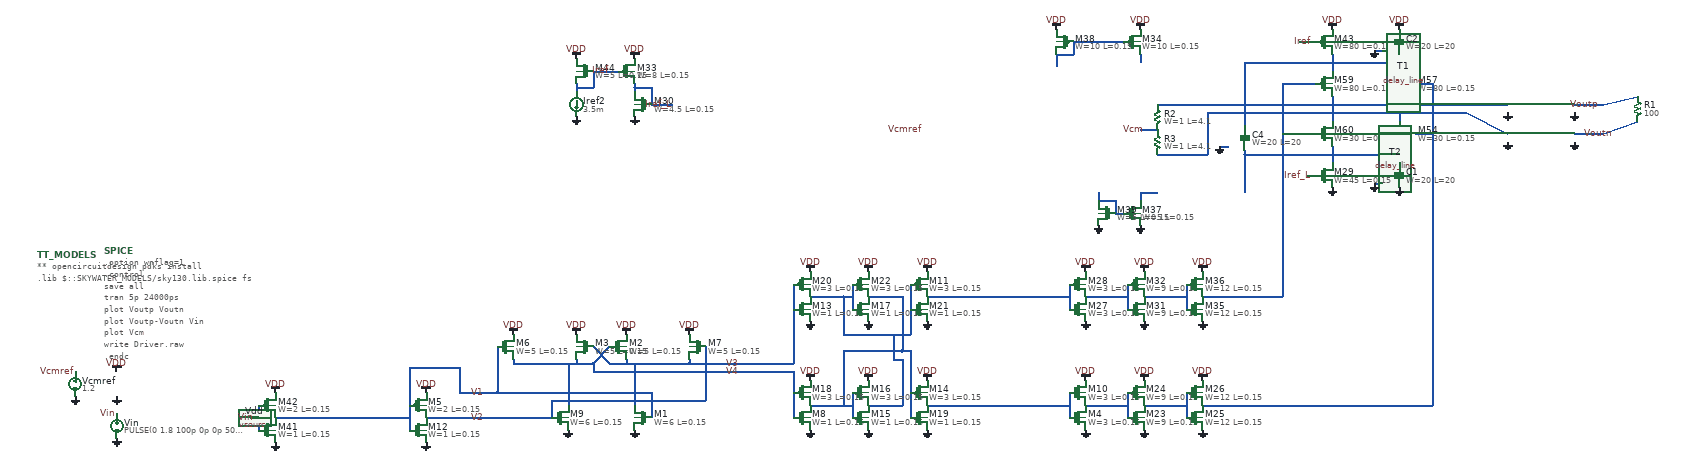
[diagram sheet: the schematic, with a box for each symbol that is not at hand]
v {xschem version=3.4.2 file_version=1.2
}
G {}
K {}
V {}
S {}
E {}
N 810 -140 1180 -140 {
lab=V2}
N 810 -140 810 -100 {
lab=V2}
N 680 -160 1050 -160 {
lab=V1}
N 1050 -160 1050 -100 {
lab=V1}
N 590 -100 810 -100 {
lab=V2}
N 590 -160 680 -160 {
lab=V1}
N 470 -130 470 -70 {
lab=V1}
N 390 -100 470 -100 {
lab=V1}
N 510 -100 590 -100 {
lab=V2}
N 470 -220 470 -130 {
lab=V1}
N 470 -220 590 -220 {
lab=V1}
N 590 -220 590 -160 {
lab=V1}
N 850 -190 850 -130 {
lab=V4}
N 1010 -190 1010 -130 {
lab=V3}
N 1390 -160 1390 -100 {
lab=V4}
N 1530 -160 1530 -100 {
lab=#net1}
N 1670 -160 1670 -100 {
lab=#net1}
N 1430 -130 1530 -130 {
lab=#net1}
N 1570 -130 1650 -130 {
lab=#net2}
N 1710 -130 1910 -130 {
lab=#net3}
N 720 -230 870 -230 {
lab=V4}
N 910 -270 950 -230 {
lab=V3}
N 910 -230 950 -270 {
lab=V4}
N 870 -230 910 -230 {
lab=V4}
N 990 -230 1140 -230 {
lab=V3}
N 950 -230 990 -230 {
lab=V3}
N 1010 -230 1010 -190 {
lab=V3}
N 850 -230 850 -190 {
lab=V4}
N 990 -240 990 -230 {
lab=V3}
N 870 -240 870 -230 {
lab=V4}
N 720 -240 720 -230 {
lab=V4}
N 1140 -240 1140 -230 {
lab=V3}
N 910 -230 910 -210 {
lab=V4}
N 1140 -230 1270 -230 {
lab=V3}
N 910 -210 1270 -210 {
lab=V4}
N 1180 -270 1180 -140 {
lab=V2}
N 680 -270 680 -160 {
lab=V1}
N 1510 -260 1650 -260 {
lab=#net1}
N 1630 -240 1650 -240 {
lab=#net2}
N 1630 -300 1630 -240 {
lab=#net2}
N 1650 -260 1670 -260 {
lab=#net1}
N 1510 -300 1670 -300 {
lab=#net2}
N 1670 -260 1670 -160 {
lab=#net1}
N 1650 -240 1650 -130 {
lab=#net2}
N 1510 -260 1510 -130 {
lab=#net1}
N 1390 -210 1390 -160 {
lab=V4}
N 1270 -210 1390 -210 {
lab=V4}
N 1390 -420 1390 -360 {
lab=V3}
N 1530 -420 1530 -360 {
lab=#net2}
N 1670 -420 1670 -360 {
lab=#net2}
N 1430 -390 1510 -390 {
lab=#net2}
N 1510 -390 1530 -390 {
lab=#net2}
N 1570 -390 1650 -390 {
lab=#net1}
N 1710 -390 1910 -390 {
lab=#net4}
N 1670 -360 1670 -300 {
lab=#net2}
N 1650 -390 1650 -260 {
lab=#net1}
N 1510 -390 1510 -300 {
lab=#net2}
N 1390 -360 1390 -230 {
lab=V3}
N 1270 -230 1390 -230 {
lab=V3}
N 1950 -390 2050 -390 {
lab=#net4}
N 2050 -420 2050 -360 {
lab=#net4}
N 2090 -390 2190 -390 {
lab=#net5}
N 2190 -420 2190 -360 {
lab=#net5}
N 2230 -390 2330 -390 {
lab=#net6}
N 2330 -420 2330 -360 {
lab=#net6}
N 2370 -390 2470 -390 {
lab=#net7}
N 110 -130 110 -70 {
lab=Vin}
N 90 -100 110 -100 {
lab=Vin}
N 150 -100 210 -100 {
lab=V1}
N 2680 -950 2840 -950 {
lab=#net8}
N 2680 -950 2680 -930 {
lab=#net8}
N 2680 -750 2680 -730 {
lab=#net9}
N 2680 -870 2680 -810 {
lab=#net10}
N 2840 -870 2840 -810 {
lab=#net11}
N 2880 -900 2920 -900 {
lab=#net12}
N 2920 -900 2920 -780 {
lab=#net12}
N 2880 -780 2920 -780 {
lab=#net12}
N 2600 -900 2640 -900 {
lab=#net7}
N 2600 -780 2640 -780 {
lab=#net7}
N 2920 -780 2920 -580 {
lab=#net12}
N 2680 -850 3000 -850 {
lab=#net10}
N 2840 -830 3000 -830 {
lab=#net11}
N 2920 -580 2920 -130 {
lab=#net12}
N 2680 -730 2840 -730 {
lab=#net9}
N 1910 -390 1950 -390 {
lab=#net4}
N 210 -100 390 -100 {
lab=V1}
N 1910 -130 1950 -130 {
lab=#net3}
N 1950 -130 2050 -130 {
lab=#net3}
N 2050 -160 2050 -100 {
lab=#net3}
N 2090 -130 2190 -130 {
lab=#net13}
N 2190 -160 2190 -100 {
lab=#net13}
N 2230 -130 2330 -130 {
lab=#net14}
N 2330 -160 2330 -100 {
lab=#net14}
N 2370 -130 2470 -130 {
lab=#net12}
N 2470 -130 2920 -130 {
lab=#net12}
N 2680 -970 2680 -950 {
lab=#net8}
N 2840 -950 2840 -930 {
lab=#net8}
N 2460 -850 2680 -850 {
lab=#net10}
N 2580 -830 2840 -830 {
lab=#net11}
N 3330 -850 3410 -870 {
lab=Voutp}
N 3260 -850 3330 -850 {
lab=Voutp}
N 3000 -850 3100 -850 {
lab=#net10}
N 3000 -830 3100 -780 {
lab=#net11}
N 3260 -780 3330 -780 {
lab=Voutn}
N 3330 -780 3410 -810 {
lab=Voutn}
N 2840 -970 2840 -950 {
lab=#net8}
N 2780 -980 2800 -980 {
lab=GND}
N 2780 -660 2800 -660 {
lab=GND}
N 2840 -750 2840 -710 {
lab=#net9}
N 2380 -830 2380 -780 {
lab=#net11}
N 2380 -780 2380 -730 {
lab=#net11}
N 2260 -730 2380 -730 {
lab=#net11}
N 2220 -790 2260 -790 {
lab=Vcm}
N 2260 -850 2460 -850 {
lab=#net10}
N 2380 -830 2580 -830 {
lab=#net11}
N 2680 -730 2680 -710 {
lab=#net9}
N 2600 -1000 2640 -1000 {
lab=Iref}
N 2620 -680 2640 -680 {
lab=Iref_L}
N 2560 -900 2600 -900 {
lab=#net7}
N 2560 -780 2600 -780 {
lab=#net7}
N 2560 -900 2560 -390 {
lab=#net7}
N 2470 -390 2560 -390 {
lab=#net7}
N 2520 -950 2680 -950 {
lab=#net8}
N 2520 -730 2680 -730 {
lab=#net9}
N 2480 -730 2520 -730 {
lab=#net9}
N 2220 -640 2260 -640 {
lab=#net15}
N 2410 -750 2430 -750 {
lab=GND}
N 2470 -730 2480 -730 {
lab=#net9}
N 2470 -740 2470 -730 {
lab=#net9}
N 2470 -730 2470 -640 {
lab=#net9}
N 2470 -950 2470 -800 {
lab=#net8}
N 2220 -970 2220 -950 {
lab=#net16}
N 2220 -640 2220 -620 {
lab=#net15}
N 1050 -890 1050 -850 {
lab=Iref_L}
N 1010 -890 1050 -890 {
lab=Iref_L}
N 1010 -890 1010 -880 {
lab=Iref_L}
N 1010 -900 1010 -890 {
lab=Iref_L}
N 870 -900 870 -880 {
lab=Iref}
N 870 -890 910 -890 {
lab=Iref}
N 910 -930 910 -890 {
lab=Iref}
N 910 -930 970 -930 {
lab=Iref}
N 1050 -850 1100 -850 {
lab=Iref_L}
N 2060 -1000 2180 -1000 {
lab=#net17}
N 2020 -970 2060 -970 {
lab=#net17}
N 2060 -1000 2060 -970 {
lab=#net17}
N 2020 -970 2020 -940 {
lab=#net17}
N 2160 -590 2180 -590 {
lab=#net18}
N 2160 -620 2160 -590 {
lab=#net18}
N 2120 -620 2160 -620 {
lab=#net18}
N 2120 -640 2120 -620 {
lab=#net18}
N 2470 -950 2520 -950 {
lab=#net8}
C {devices/gnd.sym} -230 -50 0 0 {name=l4 lab=GND}
C {devices/lab_wire.sym} -230 -110 0 0 {name=p1 sig_type=std_logic lab=Vin


}
C {devices/vsource.sym} -230 -180 0 0 {name=Vdd value=1.8
}
C {devices/vdd.sym} -230 -210 0 0 {name=l3 lab=VDD}
C {devices/gnd.sym} -230 -150 0 0 {name=l5 lab=GND}
C {devices/simulator_commands_shown.sym} -260 -500 0 0 {name=SPICE
only_toplevel=false 
value="
.option wnflag=1
.control
save all
tran 5p 24000ps
plot Voutp Voutn
plot Voutp-Voutn Vin
plot Vcm
write Driver.raw
.endc

"}
C {devices/code.sym} -420 -490 0 0 {name=TT_MODELS
only_toplevel=true
format="tcleval( @value )"
value="
** opencircuitdesign pdks install
.lib $::SKYWATER_MODELS/sky130.lib.spice fs

"
spice_ignore=false}
C {devices/vsource.sym} -230 -80 0 0 {name=Vin value="PULSE(0 1.8 100p 0p 0p 500p 1000p)"

}
C {devices/gnd.sym} 850 -70 0 0 {name=l8 lab=GND}
C {devices/gnd.sym} 1010 -70 0 0 {name=l9 lab=GND}
C {sky130_fd_pr/nfet3_01v8_lvt.sym} 830 -100 0 0 {name=M9
L=0.15
W=6
nf=1
mult=1
body=GND
ad="'int((nf+1)/2) * W/nf * 0.29'" 
pd="'2*int((nf+1)/2) * (W/nf + 0.29)'"
as="'int((nf+2)/2) * W/nf * 0.29'" 
ps="'2*int((nf+2)/2) * (W/nf + 0.29)'"
nrd="'0.29 / W'" nrs="'0.29 / W'"
sa=0 sb=0 sd=0
model=nfet_01v8_lvt
spiceprefix=X
}
C {sky130_fd_pr/nfet3_01v8_lvt.sym} 1030 -100 0 1 {name=M1
L=0.15
W=6
nf=1
mult=1
body=GND
ad="'int((nf+1)/2) * W/nf * 0.29'" 
pd="'2*int((nf+1)/2) * (W/nf + 0.29)'"
as="'int((nf+2)/2) * W/nf * 0.29'" 
ps="'2*int((nf+2)/2) * (W/nf + 0.29)'"
nrd="'0.29 / W'" nrs="'0.29 / W'"
sa=0 sb=0 sd=0
model=nfet_01v8_lvt
spiceprefix=X
}
C {sky130_fd_pr/nfet3_01v8.sym} 490 -70 0 0 {name=M12
L=0.15
W=1
body=GND
nf=1
mult=1
ad="'int((nf+1)/2) * W/nf * 0.29'" 
pd="'2*int((nf+1)/2) * (W/nf + 0.29)'"
as="'int((nf+2)/2) * W/nf * 0.29'" 
ps="'2*int((nf+2)/2) * (W/nf + 0.29)'"
nrd="'0.29 / W'" nrs="'0.29 / W'"
sa=0 sb=0 sd=0
model=nfet_01v8
spiceprefix=X
}
C {devices/gnd.sym} 510 -40 0 0 {name=l12 lab=GND}
C {devices/vdd.sym} 510 -160 0 0 {name=l13 lab=VDD}
C {devices/lab_wire.sym} 650 -100 0 0 {name=p5 sig_type=std_logic lab=V2


}
C {devices/lab_wire.sym} 650 -160 0 0 {name=p6 sig_type=std_logic lab=V1


}
C {sky130_fd_pr/pfet3_01v8.sym} 490 -130 0 0 {name=M5
L=0.15
W=2
body=VDD
nf=1
mult=1
ad="'int((nf+1)/2) * W/nf * 0.29'" 
pd="'2*int((nf+1)/2) * (W/nf + 0.29)'"
as="'int((nf+2)/2) * W/nf * 0.29'" 
ps="'2*int((nf+2)/2) * (W/nf + 0.29)'"
nrd="'0.29 / W'" nrs="'0.29 / W'"
sa=0 sb=0 sd=0
model=pfet_01v8
spiceprefix=X
}
C {sky130_fd_pr/nfet3_01v8.sym} 1410 -100 0 0 {name=M8
L=0.15
W=1
body=GND
nf=1
mult=1
ad="'int((nf+1)/2) * W/nf * 0.29'" 
pd="'2*int((nf+1)/2) * (W/nf + 0.29)'"
as="'int((nf+2)/2) * W/nf * 0.29'" 
ps="'2*int((nf+2)/2) * (W/nf + 0.29)'"
nrd="'0.29 / W'" nrs="'0.29 / W'"
sa=0 sb=0 sd=0
model=nfet_01v8
spiceprefix=X
}
C {devices/gnd.sym} 1430 -70 0 0 {name=l14 lab=GND}
C {devices/vdd.sym} 1430 -190 0 0 {name=l15 lab=VDD}
C {sky130_fd_pr/nfet3_01v8.sym} 1550 -100 0 0 {name=M15
L=0.15
W=1
body=GND
nf=1
mult=1
ad="'int((nf+1)/2) * W/nf * 0.29'" 
pd="'2*int((nf+1)/2) * (W/nf + 0.29)'"
as="'int((nf+2)/2) * W/nf * 0.29'" 
ps="'2*int((nf+2)/2) * (W/nf + 0.29)'"
nrd="'0.29 / W'" nrs="'0.29 / W'"
sa=0 sb=0 sd=0
model=nfet_01v8
spiceprefix=X
}
C {devices/gnd.sym} 1570 -70 0 0 {name=l18 lab=GND}
C {devices/vdd.sym} 1570 -190 0 0 {name=l19 lab=VDD}
C {sky130_fd_pr/nfet3_01v8.sym} 1690 -100 0 0 {name=M19
L=0.15
W=1
body=GND
nf=1
mult=1
ad="'int((nf+1)/2) * W/nf * 0.29'" 
pd="'2*int((nf+1)/2) * (W/nf + 0.29)'"
as="'int((nf+2)/2) * W/nf * 0.29'" 
ps="'2*int((nf+2)/2) * (W/nf + 0.29)'"
nrd="'0.29 / W'" nrs="'0.29 / W'"
sa=0 sb=0 sd=0
model=nfet_01v8
spiceprefix=X
}
C {devices/gnd.sym} 1710 -70 0 0 {name=l22 lab=GND}
C {devices/vdd.sym} 1710 -190 0 0 {name=l23 lab=VDD}
C {sky130_fd_pr/pfet3_01v8.sym} 890 -270 0 1 {name=M3
L=0.15
W=5
body=VDD
nf=1
mult=1
ad="'int((nf+1)/2) * W/nf * 0.29'" 
pd="'2*int((nf+1)/2) * (W/nf + 0.29)'"
as="'int((nf+2)/2) * W/nf * 0.29'" 
ps="'2*int((nf+2)/2) * (W/nf + 0.29)'"
nrd="'0.29 / W'" nrs="'0.29 / W'"
sa=0 sb=0 sd=0
model=pfet_01v8
spiceprefix=X
}
C {sky130_fd_pr/pfet3_01v8.sym} 970 -270 0 0 {name=M2
L=0.15
W=5
body=VDD
nf=1
mult=1
ad="'int((nf+1)/2) * W/nf * 0.29'" 
pd="'2*int((nf+1)/2) * (W/nf + 0.29)'"
as="'int((nf+2)/2) * W/nf * 0.29'" 
ps="'2*int((nf+2)/2) * (W/nf + 0.29)'"
nrd="'0.29 / W'" nrs="'0.29 / W'"
sa=0 sb=0 sd=0
model=pfet_01v8
spiceprefix=X
}
C {devices/vdd.sym} 990 -300 0 0 {name=l6 lab=VDD}
C {devices/vdd.sym} 870 -300 0 0 {name=l2 lab=VDD}
C {devices/vdd.sym} 720 -300 0 0 {name=l10 lab=VDD}
C {devices/vdd.sym} 1140 -300 0 0 {name=l7 lab=VDD}
C {sky130_fd_pr/nfet3_01v8.sym} 700 -270 0 0 {name=M6
L=0.15
W=5
body=GND
nf=1
mult=1
ad="'int((nf+1)/2) * W/nf * 0.29'" 
pd="'2*int((nf+1)/2) * (W/nf + 0.29)'"
as="'int((nf+2)/2) * W/nf * 0.29'" 
ps="'2*int((nf+2)/2) * (W/nf + 0.29)'"
nrd="'0.29 / W'" nrs="'0.29 / W'"
sa=0 sb=0 sd=0
model=nfet_01v8
spiceprefix=X
}
C {sky130_fd_pr/nfet3_01v8.sym} 1160 -270 0 1 {name=M7
L=0.15
W=5
body=GND
nf=1
mult=1
ad="'int((nf+1)/2) * W/nf * 0.29'" 
pd="'2*int((nf+1)/2) * (W/nf + 0.29)'"
as="'int((nf+2)/2) * W/nf * 0.29'" 
ps="'2*int((nf+2)/2) * (W/nf + 0.29)'"
nrd="'0.29 / W'" nrs="'0.29 / W'"
sa=0 sb=0 sd=0
model=nfet_01v8
spiceprefix=X
}
C {sky130_fd_pr/nfet3_01v8.sym} 1410 -360 0 0 {name=M13
L=0.15
W=1
body=GND
nf=1
mult=1
ad="'int((nf+1)/2) * W/nf * 0.29'" 
pd="'2*int((nf+1)/2) * (W/nf + 0.29)'"
as="'int((nf+2)/2) * W/nf * 0.29'" 
ps="'2*int((nf+2)/2) * (W/nf + 0.29)'"
nrd="'0.29 / W'" nrs="'0.29 / W'"
sa=0 sb=0 sd=0
model=nfet_01v8
spiceprefix=X
}
C {devices/gnd.sym} 1430 -330 0 0 {name=l16 lab=GND}
C {devices/vdd.sym} 1430 -450 0 0 {name=l17 lab=VDD}
C {sky130_fd_pr/nfet3_01v8.sym} 1550 -360 0 0 {name=M17
L=0.15
W=1
body=GND
nf=1
mult=1
ad="'int((nf+1)/2) * W/nf * 0.29'" 
pd="'2*int((nf+1)/2) * (W/nf + 0.29)'"
as="'int((nf+2)/2) * W/nf * 0.29'" 
ps="'2*int((nf+2)/2) * (W/nf + 0.29)'"
nrd="'0.29 / W'" nrs="'0.29 / W'"
sa=0 sb=0 sd=0
model=nfet_01v8
spiceprefix=X
}
C {devices/gnd.sym} 1570 -330 0 0 {name=l20 lab=GND}
C {devices/vdd.sym} 1570 -450 0 0 {name=l21 lab=VDD}
C {sky130_fd_pr/nfet3_01v8.sym} 1690 -360 0 0 {name=M21
L=0.15
W=1
body=GND
nf=1
mult=1
ad="'int((nf+1)/2) * W/nf * 0.29'" 
pd="'2*int((nf+1)/2) * (W/nf + 0.29)'"
as="'int((nf+2)/2) * W/nf * 0.29'" 
ps="'2*int((nf+2)/2) * (W/nf + 0.29)'"
nrd="'0.29 / W'" nrs="'0.29 / W'"
sa=0 sb=0 sd=0
model=nfet_01v8
spiceprefix=X
}
C {devices/gnd.sym} 1710 -330 0 0 {name=l24 lab=GND}
C {devices/vdd.sym} 1710 -450 0 0 {name=l25 lab=VDD}
C {devices/lab_wire.sym} 1260 -210 0 0 {name=p8 sig_type=std_logic lab=V4


}
C {devices/lab_wire.sym} 1260 -230 0 0 {name=p7 sig_type=std_logic lab=V3


}
C {sky130_fd_pr/nfet3_01v8.sym} 2070 -360 0 0 {name=M27
L=0.15
W=3
body=GND
nf=1
mult=1
ad="'int((nf+1)/2) * W/nf * 0.29'" 
pd="'2*int((nf+1)/2) * (W/nf + 0.29)'"
as="'int((nf+2)/2) * W/nf * 0.29'" 
ps="'2*int((nf+2)/2) * (W/nf + 0.29)'"
nrd="'0.29 / W'" nrs="'0.29 / W'"
sa=0 sb=0 sd=0
model=nfet_01v8
spiceprefix=X
}
C {devices/gnd.sym} 2090 -330 0 0 {name=l30 lab=GND}
C {devices/vdd.sym} 2090 -450 0 0 {name=l31 lab=VDD}
C {sky130_fd_pr/pfet3_01v8.sym} 2070 -420 0 0 {name=M28
L=0.15
W=3
body=VDD
nf=1
mult=3
ad="'int((nf+1)/2) * W/nf * 0.29'" 
pd="'2*int((nf+1)/2) * (W/nf + 0.29)'"
as="'int((nf+2)/2) * W/nf * 0.29'" 
ps="'2*int((nf+2)/2) * (W/nf + 0.29)'"
nrd="'0.29 / W'" nrs="'0.29 / W'"
sa=0 sb=0 sd=0
model=pfet_01v8
spiceprefix=X
}
C {sky130_fd_pr/nfet3_01v8.sym} 2210 -360 0 0 {name=M31
L=0.15
W=9
body=GND
nf=1
mult=1
ad="'int((nf+1)/2) * W/nf * 0.29'" 
pd="'2*int((nf+1)/2) * (W/nf + 0.29)'"
as="'int((nf+2)/2) * W/nf * 0.29'" 
ps="'2*int((nf+2)/2) * (W/nf + 0.29)'"
nrd="'0.29 / W'" nrs="'0.29 / W'"
sa=0 sb=0 sd=0
model=nfet_01v8
spiceprefix=X
}
C {devices/gnd.sym} 2230 -330 0 0 {name=l34 lab=GND}
C {devices/vdd.sym} 2230 -450 0 0 {name=l35 lab=VDD}
C {sky130_fd_pr/pfet3_01v8.sym} 2210 -420 0 0 {name=M32
L=0.15
W=9
body=VDD
nf=1
mult=3
ad="'int((nf+1)/2) * W/nf * 0.29'" 
pd="'2*int((nf+1)/2) * (W/nf + 0.29)'"
as="'int((nf+2)/2) * W/nf * 0.29'" 
ps="'2*int((nf+2)/2) * (W/nf + 0.29)'"
nrd="'0.29 / W'" nrs="'0.29 / W'"
sa=0 sb=0 sd=0
model=pfet_01v8
spiceprefix=X
}
C {sky130_fd_pr/nfet3_01v8.sym} 2350 -360 0 0 {name=M35
L=0.15
W=12
body=GND
nf=1
mult=1
ad="'int((nf+1)/2) * W/nf * 0.29'" 
pd="'2*int((nf+1)/2) * (W/nf + 0.29)'"
as="'int((nf+2)/2) * W/nf * 0.29'" 
ps="'2*int((nf+2)/2) * (W/nf + 0.29)'"
nrd="'0.29 / W'" nrs="'0.29 / W'"
sa=0 sb=0 sd=0
model=nfet_01v8
spiceprefix=X
}
C {devices/gnd.sym} 2370 -330 0 0 {name=l38 lab=GND}
C {devices/vdd.sym} 2370 -450 0 0 {name=l39 lab=VDD}
C {sky130_fd_pr/pfet3_01v8.sym} 2350 -420 0 0 {name=M36
L=0.15
W=12
body=VDD
nf=1
mult=3
ad="'int((nf+1)/2) * W/nf * 0.29'" 
pd="'2*int((nf+1)/2) * (W/nf + 0.29)'"
as="'int((nf+2)/2) * W/nf * 0.29'" 
ps="'2*int((nf+2)/2) * (W/nf + 0.29)'"
nrd="'0.29 / W'" nrs="'0.29 / W'"
sa=0 sb=0 sd=0
model=pfet_01v8
spiceprefix=X
}
C {devices/lab_wire.sym} 100 -100 0 0 {name=p2 sig_type=std_logic lab=Vin


}
C {sky130_fd_pr/nfet3_01v8.sym} 130 -70 0 0 {name=M41
L=0.15
W=1
body=GND
nf=1
mult=1
ad="'int((nf+1)/2) * W/nf * 0.29'" 
pd="'2*int((nf+1)/2) * (W/nf + 0.29)'"
as="'int((nf+2)/2) * W/nf * 0.29'" 
ps="'2*int((nf+2)/2) * (W/nf + 0.29)'"
nrd="'0.29 / W'" nrs="'0.29 / W'"
sa=0 sb=0 sd=0
model=nfet_01v8
spiceprefix=X
}
C {devices/gnd.sym} 150 -40 0 0 {name=l44 lab=GND}
C {devices/vdd.sym} 150 -160 0 0 {name=l45 lab=VDD}
C {sky130_fd_pr/pfet3_01v8.sym} 130 -130 0 0 {name=M42
L=0.15
W=2
body=VDD
nf=1
mult=1
ad="'int((nf+1)/2) * W/nf * 0.29'" 
pd="'2*int((nf+1)/2) * (W/nf + 0.29)'"
as="'int((nf+2)/2) * W/nf * 0.29'" 
ps="'2*int((nf+2)/2) * (W/nf + 0.29)'"
nrd="'0.29 / W'" nrs="'0.29 / W'"
sa=0 sb=0 sd=0
model=pfet_01v8
spiceprefix=X
}
C {sky130_fd_pr/nfet3_01v8.sym} 2860 -780 0 1 {name=M54
L=0.15
W=30
body=GND
nf=1
mult=1
ad="'int((nf+1)/2) * W/nf * 0.29'" 
pd="'2*int((nf+1)/2) * (W/nf + 0.29)'"
as="'int((nf+2)/2) * W/nf * 0.29'" 
ps="'2*int((nf+2)/2) * (W/nf + 0.29)'"
nrd="'0.29 / W'" nrs="'0.29 / W'"
sa=0 sb=0 sd=0
model=nfet_01v8
spiceprefix=X
}
C {sky130_fd_pr/pfet3_01v8.sym} 2860 -900 0 1 {name=M57
L=0.15
W=80
body=VDD
nf=1
mult=2
ad="'int((nf+1)/2) * W/nf * 0.29'" 
pd="'2*int((nf+1)/2) * (W/nf + 0.29)'"
as="'int((nf+2)/2) * W/nf * 0.29'" 
ps="'2*int((nf+2)/2) * (W/nf + 0.29)'"
nrd="'0.29 / W'" nrs="'0.29 / W'"
sa=0 sb=0 sd=0
model=pfet_01v8
spiceprefix=X
}
C {sky130_fd_pr/pfet3_01v8.sym} 2660 -900 0 0 {name=M59
L=0.15
W=80
body=VDD
nf=1
mult=2
ad="'int((nf+1)/2) * W/nf * 0.29'" 
pd="'2*int((nf+1)/2) * (W/nf + 0.29)'"
as="'int((nf+2)/2) * W/nf * 0.29'" 
ps="'2*int((nf+2)/2) * (W/nf + 0.29)'"
nrd="'0.29 / W'" nrs="'0.29 / W'"
sa=0 sb=0 sd=0
model=pfet_01v8
spiceprefix=X
}
C {sky130_fd_pr/nfet3_01v8.sym} 2660 -780 0 0 {name=M60
L=0.15
W=30
body=GND
nf=1
mult=1
ad="'int((nf+1)/2) * W/nf * 0.29'" 
pd="'2*int((nf+1)/2) * (W/nf + 0.29)'"
as="'int((nf+2)/2) * W/nf * 0.29'" 
ps="'2*int((nf+2)/2) * (W/nf + 0.29)'"
nrd="'0.29 / W'" nrs="'0.29 / W'"
sa=0 sb=0 sd=0
model=nfet_01v8
spiceprefix=X
}
C {sky130_fd_pr/nfet3_01v8.sym} 2070 -100 0 0 {name=M4
L=0.15
W=3
body=GND
nf=1
mult=1
ad="'int((nf+1)/2) * W/nf * 0.29'" 
pd="'2*int((nf+1)/2) * (W/nf + 0.29)'"
as="'int((nf+2)/2) * W/nf * 0.29'" 
ps="'2*int((nf+2)/2) * (W/nf + 0.29)'"
nrd="'0.29 / W'" nrs="'0.29 / W'"
sa=0 sb=0 sd=0
model=nfet_01v8
spiceprefix=X
}
C {devices/gnd.sym} 2090 -70 0 0 {name=l1 lab=GND}
C {devices/vdd.sym} 2090 -190 0 0 {name=l11 lab=VDD}
C {sky130_fd_pr/pfet3_01v8.sym} 2070 -160 0 0 {name=M10
L=0.15
W=3
body=VDD
nf=1
mult=3
ad="'int((nf+1)/2) * W/nf * 0.29'" 
pd="'2*int((nf+1)/2) * (W/nf + 0.29)'"
as="'int((nf+2)/2) * W/nf * 0.29'" 
ps="'2*int((nf+2)/2) * (W/nf + 0.29)'"
nrd="'0.29 / W'" nrs="'0.29 / W'"
sa=0 sb=0 sd=0
model=pfet_01v8
spiceprefix=X
}
C {sky130_fd_pr/nfet3_01v8.sym} 2210 -100 0 0 {name=M23
L=0.15
W=9
body=GND
nf=1
mult=1
ad="'int((nf+1)/2) * W/nf * 0.29'" 
pd="'2*int((nf+1)/2) * (W/nf + 0.29)'"
as="'int((nf+2)/2) * W/nf * 0.29'" 
ps="'2*int((nf+2)/2) * (W/nf + 0.29)'"
nrd="'0.29 / W'" nrs="'0.29 / W'"
sa=0 sb=0 sd=0
model=nfet_01v8
spiceprefix=X
}
C {devices/gnd.sym} 2230 -70 0 0 {name=l26 lab=GND}
C {devices/vdd.sym} 2230 -190 0 0 {name=l27 lab=VDD}
C {sky130_fd_pr/pfet3_01v8.sym} 2210 -160 0 0 {name=M24
L=0.15
W=9
body=VDD
nf=1
mult=3
ad="'int((nf+1)/2) * W/nf * 0.29'" 
pd="'2*int((nf+1)/2) * (W/nf + 0.29)'"
as="'int((nf+2)/2) * W/nf * 0.29'" 
ps="'2*int((nf+2)/2) * (W/nf + 0.29)'"
nrd="'0.29 / W'" nrs="'0.29 / W'"
sa=0 sb=0 sd=0
model=pfet_01v8
spiceprefix=X
}
C {sky130_fd_pr/nfet3_01v8.sym} 2350 -100 0 0 {name=M25
L=0.15
W=12
body=GND
nf=1
mult=1
ad="'int((nf+1)/2) * W/nf * 0.29'" 
pd="'2*int((nf+1)/2) * (W/nf + 0.29)'"
as="'int((nf+2)/2) * W/nf * 0.29'" 
ps="'2*int((nf+2)/2) * (W/nf + 0.29)'"
nrd="'0.29 / W'" nrs="'0.29 / W'"
sa=0 sb=0 sd=0
model=nfet_01v8
spiceprefix=X
}
C {devices/gnd.sym} 2370 -70 0 0 {name=l28 lab=GND}
C {devices/vdd.sym} 2370 -190 0 0 {name=l29 lab=VDD}
C {sky130_fd_pr/pfet3_01v8.sym} 2350 -160 0 0 {name=M26
L=0.15
W=12
body=VDD
nf=1
mult=3
ad="'int((nf+1)/2) * W/nf * 0.29'" 
pd="'2*int((nf+1)/2) * (W/nf + 0.29)'"
as="'int((nf+2)/2) * W/nf * 0.29'" 
ps="'2*int((nf+2)/2) * (W/nf + 0.29)'"
nrd="'0.29 / W'" nrs="'0.29 / W'"
sa=0 sb=0 sd=0
model=pfet_01v8
spiceprefix=X
}
C {sky130_fd_pr/pfet3_01v8.sym} 1690 -420 0 0 {name=M11
L=0.15
W=3
body=VDD
nf=1
mult=2
ad="'int((nf+1)/2) * W/nf * 0.29'" 
pd="'2*int((nf+1)/2) * (W/nf + 0.29)'"
as="'int((nf+2)/2) * W/nf * 0.29'" 
ps="'2*int((nf+2)/2) * (W/nf + 0.29)'"
nrd="'0.29 / W'" nrs="'0.29 / W'"
sa=0 sb=0 sd=0
model=pfet_01v8
spiceprefix=X
}
C {sky130_fd_pr/pfet3_01v8.sym} 1690 -160 0 0 {name=M14
L=0.15
W=3
body=VDD
nf=1
mult=2
ad="'int((nf+1)/2) * W/nf * 0.29'" 
pd="'2*int((nf+1)/2) * (W/nf + 0.29)'"
as="'int((nf+2)/2) * W/nf * 0.29'" 
ps="'2*int((nf+2)/2) * (W/nf + 0.29)'"
nrd="'0.29 / W'" nrs="'0.29 / W'"
sa=0 sb=0 sd=0
model=pfet_01v8
spiceprefix=X
}
C {sky130_fd_pr/pfet3_01v8.sym} 1550 -160 0 0 {name=M16
L=0.15
W=3
body=VDD
nf=1
mult=2
ad="'int((nf+1)/2) * W/nf * 0.29'" 
pd="'2*int((nf+1)/2) * (W/nf + 0.29)'"
as="'int((nf+2)/2) * W/nf * 0.29'" 
ps="'2*int((nf+2)/2) * (W/nf + 0.29)'"
nrd="'0.29 / W'" nrs="'0.29 / W'"
sa=0 sb=0 sd=0
model=pfet_01v8
spiceprefix=X
}
C {sky130_fd_pr/pfet3_01v8.sym} 1410 -160 0 0 {name=M18
L=0.15
W=3
body=VDD
nf=1
mult=2
ad="'int((nf+1)/2) * W/nf * 0.29'" 
pd="'2*int((nf+1)/2) * (W/nf + 0.29)'"
as="'int((nf+2)/2) * W/nf * 0.29'" 
ps="'2*int((nf+2)/2) * (W/nf + 0.29)'"
nrd="'0.29 / W'" nrs="'0.29 / W'"
sa=0 sb=0 sd=0
model=pfet_01v8
spiceprefix=X
}
C {sky130_fd_pr/pfet3_01v8.sym} 1410 -420 0 0 {name=M20
L=0.15
W=3
body=VDD
nf=1
mult=2
ad="'int((nf+1)/2) * W/nf * 0.29'" 
pd="'2*int((nf+1)/2) * (W/nf + 0.29)'"
as="'int((nf+2)/2) * W/nf * 0.29'" 
ps="'2*int((nf+2)/2) * (W/nf + 0.29)'"
nrd="'0.29 / W'" nrs="'0.29 / W'"
sa=0 sb=0 sd=0
model=pfet_01v8
spiceprefix=X
}
C {sky130_fd_pr/pfet3_01v8.sym} 1550 -420 0 0 {name=M22
L=0.15
W=3
body=VDD
nf=1
mult=2
ad="'int((nf+1)/2) * W/nf * 0.29'" 
pd="'2*int((nf+1)/2) * (W/nf + 0.29)'"
as="'int((nf+2)/2) * W/nf * 0.29'" 
ps="'2*int((nf+2)/2) * (W/nf + 0.29)'"
nrd="'0.29 / W'" nrs="'0.29 / W'"
sa=0 sb=0 sd=0
model=pfet_01v8
spiceprefix=X
}
C {devices/vdd.sym} 2680 -1030 0 0 {name=l47 lab=VDD}
C {sky130_fd_pr/pfet3_01v8.sym} 2660 -1000 0 0 {name=M43
L=0.15
W=80
body=VDD
nf=1
mult=2
ad="'int((nf+1)/2) * W/nf * 0.29'" 
pd="'2*int((nf+1)/2) * (W/nf + 0.29)'"
as="'int((nf+2)/2) * W/nf * 0.29'" 
ps="'2*int((nf+2)/2) * (W/nf + 0.29)'"
nrd="'0.29 / W'" nrs="'0.29 / W'"
sa=0 sb=0 sd=0
model=pfet_01v8
spiceprefix=X
}
C {devices/delay_line.sym} 3180 -840 0 0 {name=T1 z0=50 td=10n}
C {devices/lab_wire.sym} 3320 -850 0 0 {name=p3 sig_type=std_logic lab=Voutp


}
C {devices/res.sym} 3410 -840 0 0 {name=R1
value=100
footprint=1206
device=resistor
m=1}
C {devices/delay_line.sym} 3180 -770 0 0 {name=T2 z0=50 td=10n}
C {devices/lab_wire.sym} 3280 -780 0 1 {name=p4 sig_type=std_logic lab=Voutn


}
C {devices/gnd.sym} 3100 -830 0 0 {name=l33 lab=GND}
C {devices/gnd.sym} 3100 -760 0 0 {name=l36 lab=GND}
C {devices/gnd.sym} 3260 -760 0 0 {name=l37 lab=GND}
C {devices/gnd.sym} 3260 -830 0 0 {name=l40 lab=GND}
C {devices/vdd.sym} 2840 -1030 0 0 {name=l42 lab=VDD}
C {devices/gnd.sym} -330 -150 0 0 {name=l50 lab=GND}
C {devices/lab_wire.sym} -330 -210 0 0 {name=p11 sig_type=std_logic lab=Vcmref


}
C {devices/vsource.sym} -330 -180 0 0 {name=Vcmref value="1.2"

}
C {devices/gnd.sym} 2780 -980 0 0 {name=l41 lab=GND}
C {sky130_fd_pr/cap_var_hvt.sym} 2840 -1000 0 0 {name=C2 model=cap_var_hvt W=20 L=20 VM=1 spiceprefix=X}
C {devices/gnd.sym} 2780 -660 0 0 {name=l51 lab=GND}
C {sky130_fd_pr/cap_var_hvt.sym} 2840 -680 0 0 {name=C1 model=cap_var_hvt W=20 L=20 VM=1 spiceprefix=X}
C {sky130_fd_pr/res_generic_l1.sym} 2260 -820 0 0 {name=R2
W=1
L=4.1
model=res_generic_l1
mult=1}
C {sky130_fd_pr/res_generic_l1.sym} 2260 -760 0 0 {name=R3
W=1
L=4.1
model=res_generic_l1
mult=1}
C {devices/lab_wire.sym} 2230 -790 0 0 {name=p10 sig_type=std_logic lab=Vcm


}
C {sky130_fd_pr/nfet3_01v8.sym} 2660 -680 0 0 {name=M29
L=0.15
W=45
body=GND
nf=1
mult=1
ad="'int((nf+1)/2) * W/nf * 0.29'" 
pd="'2*int((nf+1)/2) * (W/nf + 0.29)'"
as="'int((nf+2)/2) * W/nf * 0.29'" 
ps="'2*int((nf+2)/2) * (W/nf + 0.29)'"
nrd="'0.29 / W'" nrs="'0.29 / W'"
sa=0 sb=0 sd=0
model=nfet_01v8
spiceprefix=X
}
C {devices/gnd.sym} 2840 -650 0 0 {name=l46 lab=GND}
C {devices/gnd.sym} 2680 -650 0 0 {name=l52 lab=GND}
C {devices/lab_wire.sym} 2630 -1000 0 0 {name=p14 sig_type=std_logic lab=Iref


}
C {devices/lab_wire.sym} 2630 -680 0 0 {name=p15 sig_type=std_logic lab=Iref_L


}
C {devices/gnd.sym} 2410 -750 0 0 {name=l55 lab=GND}
C {sky130_fd_pr/cap_var_hvt.sym} 2470 -770 0 0 {name=C4 model=cap_var_hvt W=20 L=20 VM=1 spiceprefix=X}
C {devices/vdd.sym} 2220 -1030 0 0 {name=l32 lab=VDD}
C {devices/gnd.sym} 2220 -560 0 0 {name=l43 lab=GND}
C {sky130_fd_pr/nfet3_01v8.sym} 1030 -850 0 1 {name=M30
L=0.15
W=4.5
body=GND
nf=1
mult=1
ad="'int((nf+1)/2) * W/nf * 0.29'" 
pd="'2*int((nf+1)/2) * (W/nf + 0.29)'"
as="'int((nf+2)/2) * W/nf * 0.29'" 
ps="'2*int((nf+2)/2) * (W/nf + 0.29)'"
nrd="'0.29 / W'" nrs="'0.29 / W'"
sa=0 sb=0 sd=0
model=nfet_01v8
spiceprefix=X
}
C {sky130_fd_pr/pfet3_01v8.sym} 990 -930 0 0 {name=M33
L=0.15
W=8
body=VDD
nf=1
mult=1
ad="'int((nf+1)/2) * W/nf * 0.29'" 
pd="'2*int((nf+1)/2) * (W/nf + 0.29)'"
as="'int((nf+2)/2) * W/nf * 0.29'" 
ps="'2*int((nf+2)/2) * (W/nf + 0.29)'"
nrd="'0.29 / W'" nrs="'0.29 / W'"
sa=0 sb=0 sd=0
model=pfet_01v8
spiceprefix=X
}
C {devices/vdd.sym} 1010 -960 0 0 {name=l53 lab=VDD}
C {sky130_fd_pr/pfet3_01v8.sym} 890 -930 0 1 {name=M44
L=0.15
W=5
body=VDD
nf=1
mult=1
ad="'int((nf+1)/2) * W/nf * 0.29'" 
pd="'2*int((nf+1)/2) * (W/nf + 0.29)'"
as="'int((nf+2)/2) * W/nf * 0.29'" 
ps="'2*int((nf+2)/2) * (W/nf + 0.29)'"
nrd="'0.29 / W'" nrs="'0.29 / W'"
sa=0 sb=0 sd=0
model=pfet_01v8
spiceprefix=X
}
C {devices/vdd.sym} 870 -960 0 0 {name=l48 lab=VDD}
C {devices/isource.sym} 870 -850 0 0 {name=Iref2 value=3.5m}
C {devices/gnd.sym} 870 -820 0 0 {name=l49 lab=GND}
C {devices/gnd.sym} 1010 -820 0 0 {name=l54 lab=GND}
C {devices/lab_wire.sym} 950 -930 0 0 {name=p12 sig_type=std_logic lab=Iref


}
C {devices/lab_wire.sym} 1100 -850 0 0 {name=p13 sig_type=std_logic lab=Iref_L


}
C {sky130_fd_pr/pfet3_01v8.sym} 2200 -1000 0 0 {name=M34
L=0.15
W=10
body=VDD
nf=1
mult=2
ad="'int((nf+1)/2) * W/nf * 0.29'" 
pd="'2*int((nf+1)/2) * (W/nf + 0.29)'"
as="'int((nf+2)/2) * W/nf * 0.29'" 
ps="'2*int((nf+2)/2) * (W/nf + 0.29)'"
nrd="'0.29 / W'" nrs="'0.29 / W'"
sa=0 sb=0 sd=0
model=pfet_01v8
spiceprefix=X
}
C {sky130_fd_pr/nfet3_01v8.sym} 2200 -590 0 0 {name=M37
L=0.15
W=5
body=GND
nf=1
mult=1
ad="'int((nf+1)/2) * W/nf * 0.29'" 
pd="'2*int((nf+1)/2) * (W/nf + 0.29)'"
as="'int((nf+2)/2) * W/nf * 0.29'" 
ps="'2*int((nf+2)/2) * (W/nf + 0.29)'"
nrd="'0.29 / W'" nrs="'0.29 / W'"
sa=0 sb=0 sd=0
model=nfet_01v8
spiceprefix=X
}
C {devices/lab_wire.sym} 1700 -790 0 0 {name=p9 sig_type=std_logic lab=Vcmref


}
C {sky130_fd_pr/pfet3_01v8.sym} 2040 -1000 0 1 {name=M38
L=0.15
W=10
body=VDD
nf=1
mult=2
ad="'int((nf+1)/2) * W/nf * 0.29'" 
pd="'2*int((nf+1)/2) * (W/nf + 0.29)'"
as="'int((nf+2)/2) * W/nf * 0.29'" 
ps="'2*int((nf+2)/2) * (W/nf + 0.29)'"
nrd="'0.29 / W'" nrs="'0.29 / W'"
sa=0 sb=0 sd=0
model=pfet_01v8
spiceprefix=X
}
C {devices/vdd.sym} 2020 -1030 0 0 {name=l56 lab=VDD}
C {sky130_fd_pr/nfet3_01v8.sym} 2140 -590 0 1 {name=M39
L=0.15
W=5
body=GND
nf=1
mult=1
ad="'int((nf+1)/2) * W/nf * 0.29'" 
pd="'2*int((nf+1)/2) * (W/nf + 0.29)'"
as="'int((nf+2)/2) * W/nf * 0.29'" 
ps="'2*int((nf+2)/2) * (W/nf + 0.29)'"
nrd="'0.29 / W'" nrs="'0.29 / W'"
sa=0 sb=0 sd=0
model=nfet_01v8
spiceprefix=X
}
C {devices/gnd.sym} 2120 -560 0 0 {name=l57 lab=GND}
